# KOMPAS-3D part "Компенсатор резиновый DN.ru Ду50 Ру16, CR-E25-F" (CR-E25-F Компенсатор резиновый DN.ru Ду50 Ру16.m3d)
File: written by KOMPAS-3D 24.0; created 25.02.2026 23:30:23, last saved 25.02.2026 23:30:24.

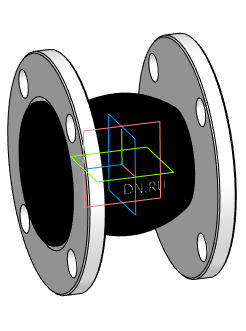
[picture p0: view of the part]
Document properties: Автор: DN.RU; Полное имя файла: D:\PROJECT CAD\DN.RU\...178(4)(ACTUALE). CR-E25-F Компенсатор резиновый DN.ru Ру10-16\DN50_PN16\CR-E25-F Компенсатор резиновый DN.ru Ду50 Ру16.m3d

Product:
- Body: Твердое тело2  | qty 1
    Масса: 4.895928
- Part/product: Компенсатор резиновый DN.ru Ду50 Ру16  | designation CR-E25-F
    Масса: 4.62
    Раздел спецификации: Прочие изделия
    Комментарий: D140-02173
    Примечание: D140-02173
    additional columns: Типовые

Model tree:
1. Твердое тело2  (labels: Твердое тело2)

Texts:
  CR-E25-F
